# Generated deterministically by seda-macro-lef-normalizer-v1; recipe orfs-ng45-fakeram-metal3-coupledl2-pg-v1.
VERSION 5.8 ;
BUSBITCHARS "[]" ;
DIVIDERCHAR "/" ;

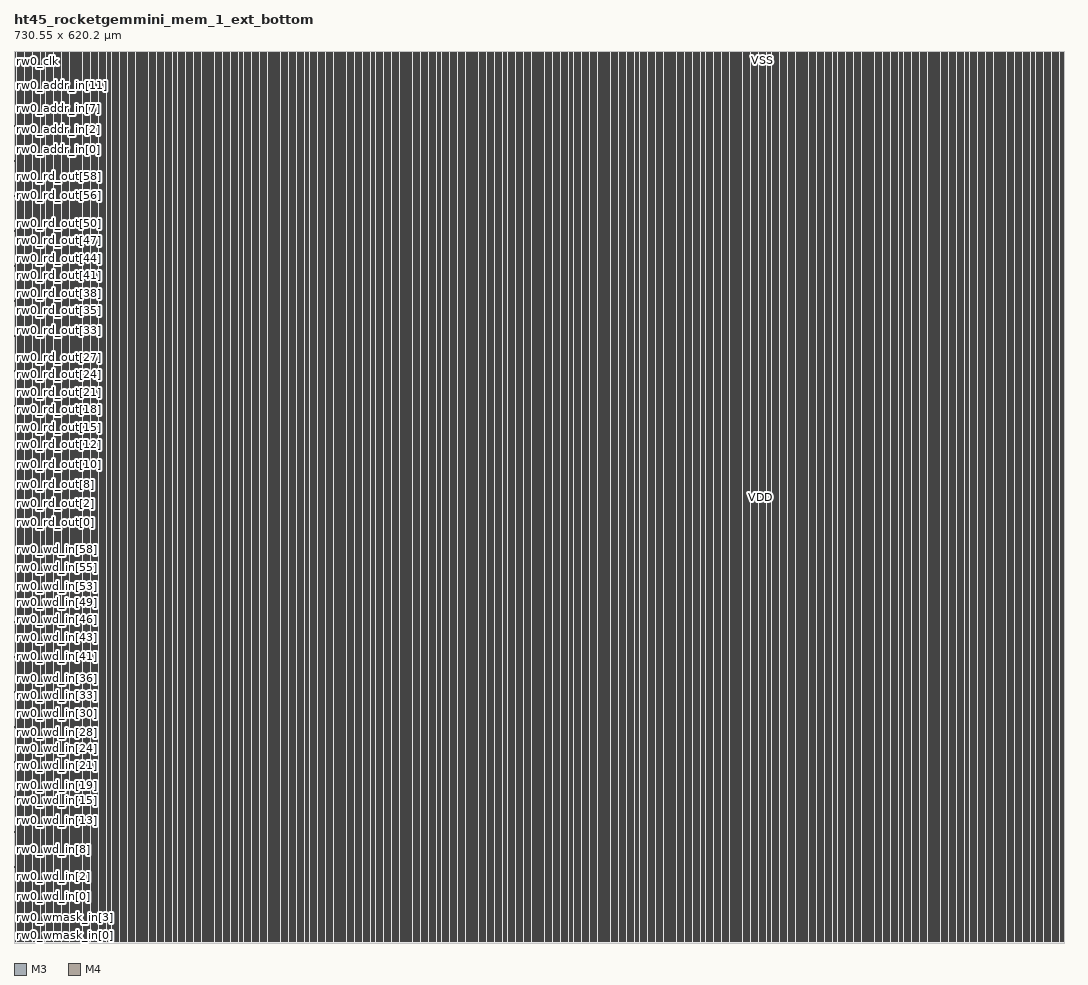
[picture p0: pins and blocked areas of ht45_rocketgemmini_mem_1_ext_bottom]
MACRO ht45_rocketgemmini_mem_1_ext_bottom
  FOREIGN ht45_rocketgemmini_mem_1_ext_bottom 0 0 ;
  CLASS BLOCK ;
  ORIGIN 0 0 ;
  SIZE 730.55 BY 620.2 ;
  SYMMETRY X Y R90 ;
  PIN rw0_wmask_in[0]
    DIRECTION INPUT ;
    USE SIGNAL ;
    SHAPE ABUTMENT ;
    PORT
      LAYER M3 ;
      RECT 0 0.035 0.07 0.105 ;
    END
  END rw0_wmask_in[0]
  PIN rw0_wmask_in[1]
    DIRECTION INPUT ;
    USE SIGNAL ;
    SHAPE ABUTMENT ;
    PORT
      LAYER M3 ;
      RECT 0 4.095 0.07 4.165 ;
    END
  END rw0_wmask_in[1]
  PIN rw0_wmask_in[2]
    DIRECTION INPUT ;
    USE SIGNAL ;
    SHAPE ABUTMENT ;
    PORT
      LAYER M3 ;
      RECT 0 8.155 0.07 8.225 ;
    END
  END rw0_wmask_in[2]
  PIN rw0_wmask_in[3]
    DIRECTION INPUT ;
    USE SIGNAL ;
    SHAPE ABUTMENT ;
    PORT
      LAYER M3 ;
      RECT 0 12.215 0.07 12.285 ;
    END
  END rw0_wmask_in[3]
  PIN rw0_wmask_in[4]
    DIRECTION INPUT ;
    USE SIGNAL ;
    SHAPE ABUTMENT ;
    PORT
      LAYER M3 ;
      RECT 0 16.275 0.07 16.345 ;
    END
  END rw0_wmask_in[4]
  PIN rw0_wmask_in[5]
    DIRECTION INPUT ;
    USE SIGNAL ;
    SHAPE ABUTMENT ;
    PORT
      LAYER M3 ;
      RECT 0 20.335 0.07 20.405 ;
    END
  END rw0_wmask_in[5]
  PIN rw0_wmask_in[6]
    DIRECTION INPUT ;
    USE SIGNAL ;
    SHAPE ABUTMENT ;
    PORT
      LAYER M3 ;
      RECT 0 24.395 0.07 24.465 ;
    END
  END rw0_wmask_in[6]
  PIN rw0_wmask_in[7]
    DIRECTION INPUT ;
    USE SIGNAL ;
    SHAPE ABUTMENT ;
    PORT
      LAYER M3 ;
      RECT 0 28.455 0.07 28.525 ;
    END
  END rw0_wmask_in[7]
  PIN rw0_wd_in[0]
    DIRECTION INPUT ;
    USE SIGNAL ;
    SHAPE ABUTMENT ;
    PORT
      LAYER M3 ;
      RECT 0 32.515 0.07 32.585 ;
    END
  END rw0_wd_in[0]
  PIN rw0_wd_in[1]
    DIRECTION INPUT ;
    USE SIGNAL ;
    SHAPE ABUTMENT ;
    PORT
      LAYER M3 ;
      RECT 0 36.575 0.07 36.645 ;
    END
  END rw0_wd_in[1]
  PIN rw0_wd_in[2]
    DIRECTION INPUT ;
    USE SIGNAL ;
    SHAPE ABUTMENT ;
    PORT
      LAYER M3 ;
      RECT 0 40.635 0.07 40.705 ;
    END
  END rw0_wd_in[2]
  PIN rw0_wd_in[3]
    DIRECTION INPUT ;
    USE SIGNAL ;
    SHAPE ABUTMENT ;
    PORT
      LAYER M3 ;
      RECT 0 44.695 0.07 44.765 ;
    END
  END rw0_wd_in[3]
  PIN rw0_wd_in[4]
    DIRECTION INPUT ;
    USE SIGNAL ;
    SHAPE ABUTMENT ;
    PORT
      LAYER M3 ;
      RECT 0 48.755 0.07 48.825 ;
    END
  END rw0_wd_in[4]
  PIN rw0_wd_in[5]
    DIRECTION INPUT ;
    USE SIGNAL ;
    SHAPE ABUTMENT ;
    PORT
      LAYER M3 ;
      RECT 0 52.815 0.07 52.885 ;
    END
  END rw0_wd_in[5]
  PIN rw0_wd_in[6]
    DIRECTION INPUT ;
    USE SIGNAL ;
    SHAPE ABUTMENT ;
    PORT
      LAYER M3 ;
      RECT 0 56.875 0.07 56.945 ;
    END
  END rw0_wd_in[6]
  PIN rw0_wd_in[7]
    DIRECTION INPUT ;
    USE SIGNAL ;
    SHAPE ABUTMENT ;
    PORT
      LAYER M3 ;
      RECT 0 60.935 0.07 61.005 ;
    END
  END rw0_wd_in[7]
  PIN rw0_wd_in[8]
    DIRECTION INPUT ;
    USE SIGNAL ;
    SHAPE ABUTMENT ;
    PORT
      LAYER M3 ;
      RECT 0 64.995 0.07 65.065 ;
    END
  END rw0_wd_in[8]
  PIN rw0_wd_in[9]
    DIRECTION INPUT ;
    USE SIGNAL ;
    SHAPE ABUTMENT ;
    PORT
      LAYER M3 ;
      RECT 0 69.055 0.07 69.125 ;
    END
  END rw0_wd_in[9]
  PIN rw0_wd_in[10]
    DIRECTION INPUT ;
    USE SIGNAL ;
    SHAPE ABUTMENT ;
    PORT
      LAYER M3 ;
      RECT 0 73.115 0.07 73.185 ;
    END
  END rw0_wd_in[10]
  PIN rw0_wd_in[11]
    DIRECTION INPUT ;
    USE SIGNAL ;
    SHAPE ABUTMENT ;
    PORT
      LAYER M3 ;
      RECT 0 77.175 0.07 77.245 ;
    END
  END rw0_wd_in[11]
  PIN rw0_wd_in[12]
    DIRECTION INPUT ;
    USE SIGNAL ;
    SHAPE ABUTMENT ;
    PORT
      LAYER M3 ;
      RECT 0 81.235 0.07 81.305 ;
    END
  END rw0_wd_in[12]
  PIN rw0_wd_in[13]
    DIRECTION INPUT ;
    USE SIGNAL ;
    SHAPE ABUTMENT ;
    PORT
      LAYER M3 ;
      RECT 0 85.295 0.07 85.365 ;
    END
  END rw0_wd_in[13]
  PIN rw0_wd_in[14]
    DIRECTION INPUT ;
    USE SIGNAL ;
    SHAPE ABUTMENT ;
    PORT
      LAYER M3 ;
      RECT 0 89.355 0.07 89.425 ;
    END
  END rw0_wd_in[14]
  PIN rw0_wd_in[15]
    DIRECTION INPUT ;
    USE SIGNAL ;
    SHAPE ABUTMENT ;
    PORT
      LAYER M3 ;
      RECT 0 93.415 0.07 93.485 ;
    END
  END rw0_wd_in[15]
  PIN rw0_wd_in[16]
    DIRECTION INPUT ;
    USE SIGNAL ;
    SHAPE ABUTMENT ;
    PORT
      LAYER M3 ;
      RECT 0 97.475 0.07 97.545 ;
    END
  END rw0_wd_in[16]
  PIN rw0_wd_in[17]
    DIRECTION INPUT ;
    USE SIGNAL ;
    SHAPE ABUTMENT ;
    PORT
      LAYER M3 ;
      RECT 0 101.535 0.07 101.605 ;
    END
  END rw0_wd_in[17]
  PIN rw0_wd_in[18]
    DIRECTION INPUT ;
    USE SIGNAL ;
    SHAPE ABUTMENT ;
    PORT
      LAYER M3 ;
      RECT 0 105.595 0.07 105.665 ;
    END
  END rw0_wd_in[18]
  PIN rw0_wd_in[19]
    DIRECTION INPUT ;
    USE SIGNAL ;
    SHAPE ABUTMENT ;
    PORT
      LAYER M3 ;
      RECT 0 109.655 0.07 109.725 ;
    END
  END rw0_wd_in[19]
  PIN rw0_wd_in[20]
    DIRECTION INPUT ;
    USE SIGNAL ;
    SHAPE ABUTMENT ;
    PORT
      LAYER M3 ;
      RECT 0 113.715 0.07 113.785 ;
    END
  END rw0_wd_in[20]
  PIN rw0_wd_in[21]
    DIRECTION INPUT ;
    USE SIGNAL ;
    SHAPE ABUTMENT ;
    PORT
      LAYER M3 ;
      RECT 0 117.775 0.07 117.845 ;
    END
  END rw0_wd_in[21]
  PIN rw0_wd_in[22]
    DIRECTION INPUT ;
    USE SIGNAL ;
    SHAPE ABUTMENT ;
    PORT
      LAYER M3 ;
      RECT 0 121.835 0.07 121.905 ;
    END
  END rw0_wd_in[22]
  PIN rw0_wd_in[23]
    DIRECTION INPUT ;
    USE SIGNAL ;
    SHAPE ABUTMENT ;
    PORT
      LAYER M3 ;
      RECT 0 125.895 0.07 125.965 ;
    END
  END rw0_wd_in[23]
  PIN rw0_wd_in[24]
    DIRECTION INPUT ;
    USE SIGNAL ;
    SHAPE ABUTMENT ;
    PORT
      LAYER M3 ;
      RECT 0 129.955 0.07 130.025 ;
    END
  END rw0_wd_in[24]
  PIN rw0_wd_in[25]
    DIRECTION INPUT ;
    USE SIGNAL ;
    SHAPE ABUTMENT ;
    PORT
      LAYER M3 ;
      RECT 0 134.015 0.07 134.085 ;
    END
  END rw0_wd_in[25]
  PIN rw0_wd_in[26]
    DIRECTION INPUT ;
    USE SIGNAL ;
    SHAPE ABUTMENT ;
    PORT
      LAYER M3 ;
      RECT 0 138.075 0.07 138.145 ;
    END
  END rw0_wd_in[26]
  PIN rw0_wd_in[27]
    DIRECTION INPUT ;
    USE SIGNAL ;
    SHAPE ABUTMENT ;
    PORT
      LAYER M3 ;
      RECT 0 142.135 0.07 142.205 ;
    END
  END rw0_wd_in[27]
  PIN rw0_wd_in[28]
    DIRECTION INPUT ;
    USE SIGNAL ;
    SHAPE ABUTMENT ;
    PORT
      LAYER M3 ;
      RECT 0 146.195 0.07 146.265 ;
    END
  END rw0_wd_in[28]
  PIN rw0_wd_in[29]
    DIRECTION INPUT ;
    USE SIGNAL ;
    SHAPE ABUTMENT ;
    PORT
      LAYER M3 ;
      RECT 0 150.255 0.07 150.325 ;
    END
  END rw0_wd_in[29]
  PIN rw0_wd_in[30]
    DIRECTION INPUT ;
    USE SIGNAL ;
    SHAPE ABUTMENT ;
    PORT
      LAYER M3 ;
      RECT 0 154.315 0.07 154.385 ;
    END
  END rw0_wd_in[30]
  PIN rw0_wd_in[31]
    DIRECTION INPUT ;
    USE SIGNAL ;
    SHAPE ABUTMENT ;
    PORT
      LAYER M3 ;
      RECT 0 158.375 0.07 158.445 ;
    END
  END rw0_wd_in[31]
  PIN rw0_wd_in[32]
    DIRECTION INPUT ;
    USE SIGNAL ;
    SHAPE ABUTMENT ;
    PORT
      LAYER M3 ;
      RECT 0 162.435 0.07 162.505 ;
    END
  END rw0_wd_in[32]
  PIN rw0_wd_in[33]
    DIRECTION INPUT ;
    USE SIGNAL ;
    SHAPE ABUTMENT ;
    PORT
      LAYER M3 ;
      RECT 0 166.495 0.07 166.565 ;
    END
  END rw0_wd_in[33]
  PIN rw0_wd_in[34]
    DIRECTION INPUT ;
    USE SIGNAL ;
    SHAPE ABUTMENT ;
    PORT
      LAYER M3 ;
      RECT 0 170.555 0.07 170.625 ;
    END
  END rw0_wd_in[34]
  PIN rw0_wd_in[35]
    DIRECTION INPUT ;
    USE SIGNAL ;
    SHAPE ABUTMENT ;
    PORT
      LAYER M3 ;
      RECT 0 174.615 0.07 174.685 ;
    END
  END rw0_wd_in[35]
  PIN rw0_wd_in[36]
    DIRECTION INPUT ;
    USE SIGNAL ;
    SHAPE ABUTMENT ;
    PORT
      LAYER M3 ;
      RECT 0 178.675 0.07 178.745 ;
    END
  END rw0_wd_in[36]
  PIN rw0_wd_in[37]
    DIRECTION INPUT ;
    USE SIGNAL ;
    SHAPE ABUTMENT ;
    PORT
      LAYER M3 ;
      RECT 0 182.735 0.07 182.805 ;
    END
  END rw0_wd_in[37]
  PIN rw0_wd_in[38]
    DIRECTION INPUT ;
    USE SIGNAL ;
    SHAPE ABUTMENT ;
    PORT
      LAYER M3 ;
      RECT 0 186.795 0.07 186.865 ;
    END
  END rw0_wd_in[38]
  PIN rw0_wd_in[39]
    DIRECTION INPUT ;
    USE SIGNAL ;
    SHAPE ABUTMENT ;
    PORT
      LAYER M3 ;
      RECT 0 190.855 0.07 190.925 ;
    END
  END rw0_wd_in[39]
  PIN rw0_wd_in[40]
    DIRECTION INPUT ;
    USE SIGNAL ;
    SHAPE ABUTMENT ;
    PORT
      LAYER M3 ;
      RECT 0 194.915 0.07 194.985 ;
    END
  END rw0_wd_in[40]
  PIN rw0_wd_in[41]
    DIRECTION INPUT ;
    USE SIGNAL ;
    SHAPE ABUTMENT ;
    PORT
      LAYER M3 ;
      RECT 0 198.975 0.07 199.045 ;
    END
  END rw0_wd_in[41]
  PIN rw0_wd_in[42]
    DIRECTION INPUT ;
    USE SIGNAL ;
    SHAPE ABUTMENT ;
    PORT
      LAYER M3 ;
      RECT 0 203.035 0.07 203.105 ;
    END
  END rw0_wd_in[42]
  PIN rw0_wd_in[43]
    DIRECTION INPUT ;
    USE SIGNAL ;
    SHAPE ABUTMENT ;
    PORT
      LAYER M3 ;
      RECT 0 207.095 0.07 207.165 ;
    END
  END rw0_wd_in[43]
  PIN rw0_wd_in[44]
    DIRECTION INPUT ;
    USE SIGNAL ;
    SHAPE ABUTMENT ;
    PORT
      LAYER M3 ;
      RECT 0 211.155 0.07 211.225 ;
    END
  END rw0_wd_in[44]
  PIN rw0_wd_in[45]
    DIRECTION INPUT ;
    USE SIGNAL ;
    SHAPE ABUTMENT ;
    PORT
      LAYER M3 ;
      RECT 0 215.215 0.07 215.285 ;
    END
  END rw0_wd_in[45]
  PIN rw0_wd_in[46]
    DIRECTION INPUT ;
    USE SIGNAL ;
    SHAPE ABUTMENT ;
    PORT
      LAYER M3 ;
      RECT 0 219.275 0.07 219.345 ;
    END
  END rw0_wd_in[46]
  PIN rw0_wd_in[47]
    DIRECTION INPUT ;
    USE SIGNAL ;
    SHAPE ABUTMENT ;
    PORT
      LAYER M3 ;
      RECT 0 223.335 0.07 223.405 ;
    END
  END rw0_wd_in[47]
  PIN rw0_wd_in[48]
    DIRECTION INPUT ;
    USE SIGNAL ;
    SHAPE ABUTMENT ;
    PORT
      LAYER M3 ;
      RECT 0 227.395 0.07 227.465 ;
    END
  END rw0_wd_in[48]
  PIN rw0_wd_in[49]
    DIRECTION INPUT ;
    USE SIGNAL ;
    SHAPE ABUTMENT ;
    PORT
      LAYER M3 ;
      RECT 0 231.455 0.07 231.525 ;
    END
  END rw0_wd_in[49]
  PIN rw0_wd_in[50]
    DIRECTION INPUT ;
    USE SIGNAL ;
    SHAPE ABUTMENT ;
    PORT
      LAYER M3 ;
      RECT 0 235.515 0.07 235.585 ;
    END
  END rw0_wd_in[50]
  PIN rw0_wd_in[51]
    DIRECTION INPUT ;
    USE SIGNAL ;
    SHAPE ABUTMENT ;
    PORT
      LAYER M3 ;
      RECT 0 239.575 0.07 239.645 ;
    END
  END rw0_wd_in[51]
  PIN rw0_wd_in[52]
    DIRECTION INPUT ;
    USE SIGNAL ;
    SHAPE ABUTMENT ;
    PORT
      LAYER M3 ;
      RECT 0 243.635 0.07 243.705 ;
    END
  END rw0_wd_in[52]
  PIN rw0_wd_in[53]
    DIRECTION INPUT ;
    USE SIGNAL ;
    SHAPE ABUTMENT ;
    PORT
      LAYER M3 ;
      RECT 0 247.695 0.07 247.765 ;
    END
  END rw0_wd_in[53]
  PIN rw0_wd_in[54]
    DIRECTION INPUT ;
    USE SIGNAL ;
    SHAPE ABUTMENT ;
    PORT
      LAYER M3 ;
      RECT 0 251.755 0.07 251.825 ;
    END
  END rw0_wd_in[54]
  PIN rw0_wd_in[55]
    DIRECTION INPUT ;
    USE SIGNAL ;
    SHAPE ABUTMENT ;
    PORT
      LAYER M3 ;
      RECT 0 255.815 0.07 255.885 ;
    END
  END rw0_wd_in[55]
  PIN rw0_wd_in[56]
    DIRECTION INPUT ;
    USE SIGNAL ;
    SHAPE ABUTMENT ;
    PORT
      LAYER M3 ;
      RECT 0 259.875 0.07 259.945 ;
    END
  END rw0_wd_in[56]
  PIN rw0_wd_in[57]
    DIRECTION INPUT ;
    USE SIGNAL ;
    SHAPE ABUTMENT ;
    PORT
      LAYER M3 ;
      RECT 0 263.935 0.07 264.005 ;
    END
  END rw0_wd_in[57]
  PIN rw0_wd_in[58]
    DIRECTION INPUT ;
    USE SIGNAL ;
    SHAPE ABUTMENT ;
    PORT
      LAYER M3 ;
      RECT 0 267.995 0.07 268.065 ;
    END
  END rw0_wd_in[58]
  PIN rw0_wd_in[59]
    DIRECTION INPUT ;
    USE SIGNAL ;
    SHAPE ABUTMENT ;
    PORT
      LAYER M3 ;
      RECT 0 272.055 0.07 272.125 ;
    END
  END rw0_wd_in[59]
  PIN rw0_wd_in[60]
    DIRECTION INPUT ;
    USE SIGNAL ;
    SHAPE ABUTMENT ;
    PORT
      LAYER M3 ;
      RECT 0 276.115 0.07 276.185 ;
    END
  END rw0_wd_in[60]
  PIN rw0_wd_in[61]
    DIRECTION INPUT ;
    USE SIGNAL ;
    SHAPE ABUTMENT ;
    PORT
      LAYER M3 ;
      RECT 0 280.175 0.07 280.245 ;
    END
  END rw0_wd_in[61]
  PIN rw0_wd_in[62]
    DIRECTION INPUT ;
    USE SIGNAL ;
    SHAPE ABUTMENT ;
    PORT
      LAYER M3 ;
      RECT 0 284.235 0.07 284.305 ;
    END
  END rw0_wd_in[62]
  PIN rw0_wd_in[63]
    DIRECTION INPUT ;
    USE SIGNAL ;
    SHAPE ABUTMENT ;
    PORT
      LAYER M3 ;
      RECT 0 288.295 0.07 288.365 ;
    END
  END rw0_wd_in[63]
  PIN rw0_rd_out[0]
    DIRECTION OUTPUT ;
    USE SIGNAL ;
    SHAPE ABUTMENT ;
    PORT
      LAYER M3 ;
      RECT 0 292.355 0.07 292.425 ;
    END
  END rw0_rd_out[0]
  PIN rw0_rd_out[1]
    DIRECTION OUTPUT ;
    USE SIGNAL ;
    SHAPE ABUTMENT ;
    PORT
      LAYER M3 ;
      RECT 0 296.415 0.07 296.485 ;
    END
  END rw0_rd_out[1]
  PIN rw0_rd_out[2]
    DIRECTION OUTPUT ;
    USE SIGNAL ;
    SHAPE ABUTMENT ;
    PORT
      LAYER M3 ;
      RECT 0 300.475 0.07 300.545 ;
    END
  END rw0_rd_out[2]
  PIN rw0_rd_out[3]
    DIRECTION OUTPUT ;
    USE SIGNAL ;
    SHAPE ABUTMENT ;
    PORT
      LAYER M3 ;
      RECT 0 304.535 0.07 304.605 ;
    END
  END rw0_rd_out[3]
  PIN rw0_rd_out[4]
    DIRECTION OUTPUT ;
    USE SIGNAL ;
    SHAPE ABUTMENT ;
    PORT
      LAYER M3 ;
      RECT 0 308.595 0.07 308.665 ;
    END
  END rw0_rd_out[4]
  PIN rw0_rd_out[5]
    DIRECTION OUTPUT ;
    USE SIGNAL ;
    SHAPE ABUTMENT ;
    PORT
      LAYER M3 ;
      RECT 0 312.655 0.07 312.725 ;
    END
  END rw0_rd_out[5]
  PIN rw0_rd_out[6]
    DIRECTION OUTPUT ;
    USE SIGNAL ;
    SHAPE ABUTMENT ;
    PORT
      LAYER M3 ;
      RECT 0 316.715 0.07 316.785 ;
    END
  END rw0_rd_out[6]
  PIN rw0_rd_out[7]
    DIRECTION OUTPUT ;
    USE SIGNAL ;
    SHAPE ABUTMENT ;
    PORT
      LAYER M3 ;
      RECT 0 320.775 0.07 320.845 ;
    END
  END rw0_rd_out[7]
  PIN rw0_rd_out[8]
    DIRECTION OUTPUT ;
    USE SIGNAL ;
    SHAPE ABUTMENT ;
    PORT
      LAYER M3 ;
      RECT 0 324.835 0.07 324.905 ;
    END
  END rw0_rd_out[8]
  PIN rw0_rd_out[9]
    DIRECTION OUTPUT ;
    USE SIGNAL ;
    SHAPE ABUTMENT ;
    PORT
      LAYER M3 ;
      RECT 0 328.895 0.07 328.965 ;
    END
  END rw0_rd_out[9]
  PIN rw0_rd_out[10]
    DIRECTION OUTPUT ;
    USE SIGNAL ;
    SHAPE ABUTMENT ;
    PORT
      LAYER M3 ;
      RECT 0 332.955 0.07 333.025 ;
    END
  END rw0_rd_out[10]
  PIN rw0_rd_out[11]
    DIRECTION OUTPUT ;
    USE SIGNAL ;
    SHAPE ABUTMENT ;
    PORT
      LAYER M3 ;
      RECT 0 337.015 0.07 337.085 ;
    END
  END rw0_rd_out[11]
  PIN rw0_rd_out[12]
    DIRECTION OUTPUT ;
    USE SIGNAL ;
    SHAPE ABUTMENT ;
    PORT
      LAYER M3 ;
      RECT 0 341.075 0.07 341.145 ;
    END
  END rw0_rd_out[12]
  PIN rw0_rd_out[13]
    DIRECTION OUTPUT ;
    USE SIGNAL ;
    SHAPE ABUTMENT ;
    PORT
      LAYER M3 ;
      RECT 0 345.135 0.07 345.205 ;
    END
  END rw0_rd_out[13]
  PIN rw0_rd_out[14]
    DIRECTION OUTPUT ;
    USE SIGNAL ;
    SHAPE ABUTMENT ;
    PORT
      LAYER M3 ;
      RECT 0 349.195 0.07 349.265 ;
    END
  END rw0_rd_out[14]
  PIN rw0_rd_out[15]
    DIRECTION OUTPUT ;
    USE SIGNAL ;
    SHAPE ABUTMENT ;
    PORT
      LAYER M3 ;
      RECT 0 353.255 0.07 353.325 ;
    END
  END rw0_rd_out[15]
  PIN rw0_rd_out[16]
    DIRECTION OUTPUT ;
    USE SIGNAL ;
    SHAPE ABUTMENT ;
    PORT
      LAYER M3 ;
      RECT 0 357.315 0.07 357.385 ;
    END
  END rw0_rd_out[16]
  PIN rw0_rd_out[17]
    DIRECTION OUTPUT ;
    USE SIGNAL ;
    SHAPE ABUTMENT ;
    PORT
      LAYER M3 ;
      RECT 0 361.375 0.07 361.445 ;
    END
  END rw0_rd_out[17]
  PIN rw0_rd_out[18]
    DIRECTION OUTPUT ;
    USE SIGNAL ;
    SHAPE ABUTMENT ;
    PORT
      LAYER M3 ;
      RECT 0 365.435 0.07 365.505 ;
    END
  END rw0_rd_out[18]
  PIN rw0_rd_out[19]
    DIRECTION OUTPUT ;
    USE SIGNAL ;
    SHAPE ABUTMENT ;
    PORT
      LAYER M3 ;
      RECT 0 369.495 0.07 369.565 ;
    END
  END rw0_rd_out[19]
  PIN rw0_rd_out[20]
    DIRECTION OUTPUT ;
    USE SIGNAL ;
    SHAPE ABUTMENT ;
    PORT
      LAYER M3 ;
      RECT 0 373.555 0.07 373.625 ;
    END
  END rw0_rd_out[20]
  PIN rw0_rd_out[21]
    DIRECTION OUTPUT ;
    USE SIGNAL ;
    SHAPE ABUTMENT ;
    PORT
      LAYER M3 ;
      RECT 0 377.615 0.07 377.685 ;
    END
  END rw0_rd_out[21]
  PIN rw0_rd_out[22]
    DIRECTION OUTPUT ;
    USE SIGNAL ;
    SHAPE ABUTMENT ;
    PORT
      LAYER M3 ;
      RECT 0 381.675 0.07 381.745 ;
    END
  END rw0_rd_out[22]
  PIN rw0_rd_out[23]
    DIRECTION OUTPUT ;
    USE SIGNAL ;
    SHAPE ABUTMENT ;
    PORT
      LAYER M3 ;
      RECT 0 385.735 0.07 385.805 ;
    END
  END rw0_rd_out[23]
  PIN rw0_rd_out[24]
    DIRECTION OUTPUT ;
    USE SIGNAL ;
    SHAPE ABUTMENT ;
    PORT
      LAYER M3 ;
      RECT 0 389.795 0.07 389.865 ;
    END
  END rw0_rd_out[24]
  PIN rw0_rd_out[25]
    DIRECTION OUTPUT ;
    USE SIGNAL ;
    SHAPE ABUTMENT ;
    PORT
      LAYER M3 ;
      RECT 0 393.855 0.07 393.925 ;
    END
  END rw0_rd_out[25]
  PIN rw0_rd_out[26]
    DIRECTION OUTPUT ;
    USE SIGNAL ;
    SHAPE ABUTMENT ;
    PORT
      LAYER M3 ;
      RECT 0 397.915 0.07 397.985 ;
    END
  END rw0_rd_out[26]
  PIN rw0_rd_out[27]
    DIRECTION OUTPUT ;
    USE SIGNAL ;
    SHAPE ABUTMENT ;
    PORT
      LAYER M3 ;
      RECT 0 401.975 0.07 402.045 ;
    END
  END rw0_rd_out[27]
  PIN rw0_rd_out[28]
    DIRECTION OUTPUT ;
    USE SIGNAL ;
    SHAPE ABUTMENT ;
    PORT
      LAYER M3 ;
      RECT 0 406.035 0.07 406.105 ;
    END
  END rw0_rd_out[28]
  PIN rw0_rd_out[29]
    DIRECTION OUTPUT ;
    USE SIGNAL ;
    SHAPE ABUTMENT ;
    PORT
      LAYER M3 ;
      RECT 0 410.095 0.07 410.165 ;
    END
  END rw0_rd_out[29]
  PIN rw0_rd_out[30]
    DIRECTION OUTPUT ;
    USE SIGNAL ;
    SHAPE ABUTMENT ;
    PORT
      LAYER M3 ;
      RECT 0 414.155 0.07 414.225 ;
    END
  END rw0_rd_out[30]
  PIN rw0_rd_out[31]
    DIRECTION OUTPUT ;
    USE SIGNAL ;
    SHAPE ABUTMENT ;
    PORT
      LAYER M3 ;
      RECT 0 418.215 0.07 418.285 ;
    END
  END rw0_rd_out[31]
  PIN rw0_rd_out[32]
    DIRECTION OUTPUT ;
    USE SIGNAL ;
    SHAPE ABUTMENT ;
    PORT
      LAYER M3 ;
      RECT 0 422.275 0.07 422.345 ;
    END
  END rw0_rd_out[32]
  PIN rw0_rd_out[33]
    DIRECTION OUTPUT ;
    USE SIGNAL ;
    SHAPE ABUTMENT ;
    PORT
      LAYER M3 ;
      RECT 0 426.335 0.07 426.405 ;
    END
  END rw0_rd_out[33]
  PIN rw0_rd_out[34]
    DIRECTION OUTPUT ;
    USE SIGNAL ;
    SHAPE ABUTMENT ;
    PORT
      LAYER M3 ;
      RECT 0 430.395 0.07 430.465 ;
    END
  END rw0_rd_out[34]
  PIN rw0_rd_out[35]
    DIRECTION OUTPUT ;
    USE SIGNAL ;
    SHAPE ABUTMENT ;
    PORT
      LAYER M3 ;
      RECT 0 434.455 0.07 434.525 ;
    END
  END rw0_rd_out[35]
  PIN rw0_rd_out[36]
    DIRECTION OUTPUT ;
    USE SIGNAL ;
    SHAPE ABUTMENT ;
    PORT
      LAYER M3 ;
      RECT 0 438.515 0.07 438.585 ;
    END
  END rw0_rd_out[36]
  PIN rw0_rd_out[37]
    DIRECTION OUTPUT ;
    USE SIGNAL ;
    SHAPE ABUTMENT ;
    PORT
      LAYER M3 ;
      RECT 0 442.575 0.07 442.645 ;
    END
  END rw0_rd_out[37]
  PIN rw0_rd_out[38]
    DIRECTION OUTPUT ;
    USE SIGNAL ;
    SHAPE ABUTMENT ;
    PORT
      LAYER M3 ;
      RECT 0 446.635 0.07 446.705 ;
    END
  END rw0_rd_out[38]
  PIN rw0_rd_out[39]
    DIRECTION OUTPUT ;
    USE SIGNAL ;
    SHAPE ABUTMENT ;
    PORT
      LAYER M3 ;
      RECT 0 450.695 0.07 450.765 ;
    END
  END rw0_rd_out[39]
  PIN rw0_rd_out[40]
    DIRECTION OUTPUT ;
    USE SIGNAL ;
    SHAPE ABUTMENT ;
    PORT
      LAYER M3 ;
      RECT 0 454.755 0.07 454.825 ;
    END
  END rw0_rd_out[40]
  PIN rw0_rd_out[41]
    DIRECTION OUTPUT ;
    USE SIGNAL ;
    SHAPE ABUTMENT ;
    PORT
      LAYER M3 ;
      RECT 0 458.815 0.07 458.885 ;
    END
  END rw0_rd_out[41]
  PIN rw0_rd_out[42]
    DIRECTION OUTPUT ;
    USE SIGNAL ;
    SHAPE ABUTMENT ;
    PORT
      LAYER M3 ;
      RECT 0 462.875 0.07 462.945 ;
    END
  END rw0_rd_out[42]
  PIN rw0_rd_out[43]
    DIRECTION OUTPUT ;
    USE SIGNAL ;
    SHAPE ABUTMENT ;
    PORT
      LAYER M3 ;
      RECT 0 466.935 0.07 467.005 ;
    END
  END rw0_rd_out[43]
  PIN rw0_rd_out[44]
    DIRECTION OUTPUT ;
    USE SIGNAL ;
    SHAPE ABUTMENT ;
    PORT
      LAYER M3 ;
      RECT 0 470.995 0.07 471.065 ;
    END
  END rw0_rd_out[44]
  PIN rw0_rd_out[45]
    DIRECTION OUTPUT ;
    USE SIGNAL ;
    SHAPE ABUTMENT ;
    PORT
      LAYER M3 ;
      RECT 0 475.055 0.07 475.125 ;
    END
  END rw0_rd_out[45]
  PIN rw0_rd_out[46]
    DIRECTION OUTPUT ;
    USE SIGNAL ;
    SHAPE ABUTMENT ;
    PORT
      LAYER M3 ;
      RECT 0 479.115 0.07 479.185 ;
    END
  END rw0_rd_out[46]
  PIN rw0_rd_out[47]
    DIRECTION OUTPUT ;
    USE SIGNAL ;
    SHAPE ABUTMENT ;
    PORT
      LAYER M3 ;
      RECT 0 483.175 0.07 483.245 ;
    END
  END rw0_rd_out[47]
  PIN rw0_rd_out[48]
    DIRECTION OUTPUT ;
    USE SIGNAL ;
    SHAPE ABUTMENT ;
    PORT
      LAYER M3 ;
      RECT 0 487.235 0.07 487.305 ;
    END
  END rw0_rd_out[48]
  PIN rw0_rd_out[49]
    DIRECTION OUTPUT ;
    USE SIGNAL ;
    SHAPE ABUTMENT ;
    PORT
      LAYER M3 ;
      RECT 0 491.295 0.07 491.365 ;
    END
  END rw0_rd_out[49]
  PIN rw0_rd_out[50]
    DIRECTION OUTPUT ;
    USE SIGNAL ;
    SHAPE ABUTMENT ;
    PORT
      LAYER M3 ;
      RECT 0 495.355 0.07 495.425 ;
    END
  END rw0_rd_out[50]
  PIN rw0_rd_out[51]
    DIRECTION OUTPUT ;
    USE SIGNAL ;
    SHAPE ABUTMENT ;
    PORT
      LAYER M3 ;
      RECT 0 499.415 0.07 499.485 ;
    END
  END rw0_rd_out[51]
  PIN rw0_rd_out[52]
    DIRECTION OUTPUT ;
    USE SIGNAL ;
    SHAPE ABUTMENT ;
    PORT
      LAYER M3 ;
      RECT 0 503.475 0.07 503.545 ;
    END
  END rw0_rd_out[52]
  PIN rw0_rd_out[53]
    DIRECTION OUTPUT ;
    USE SIGNAL ;
    SHAPE ABUTMENT ;
    PORT
      LAYER M3 ;
      RECT 0 507.535 0.07 507.605 ;
    END
  END rw0_rd_out[53]
  PIN rw0_rd_out[54]
    DIRECTION OUTPUT ;
    USE SIGNAL ;
    SHAPE ABUTMENT ;
    PORT
      LAYER M3 ;
      RECT 0 511.595 0.07 511.665 ;
    END
  END rw0_rd_out[54]
  PIN rw0_rd_out[55]
    DIRECTION OUTPUT ;
    USE SIGNAL ;
    SHAPE ABUTMENT ;
    PORT
      LAYER M3 ;
      RECT 0 515.655 0.07 515.725 ;
    END
  END rw0_rd_out[55]
  PIN rw0_rd_out[56]
    DIRECTION OUTPUT ;
    USE SIGNAL ;
    SHAPE ABUTMENT ;
    PORT
      LAYER M3 ;
      RECT 0 519.715 0.07 519.785 ;
    END
  END rw0_rd_out[56]
  PIN rw0_rd_out[57]
    DIRECTION OUTPUT ;
    USE SIGNAL ;
    SHAPE ABUTMENT ;
    PORT
      LAYER M3 ;
      RECT 0 523.775 0.07 523.845 ;
    END
  END rw0_rd_out[57]
  PIN rw0_rd_out[58]
    DIRECTION OUTPUT ;
    USE SIGNAL ;
    SHAPE ABUTMENT ;
    PORT
      LAYER M3 ;
      RECT 0 527.835 0.07 527.905 ;
    END
  END rw0_rd_out[58]
  PIN rw0_rd_out[59]
    DIRECTION OUTPUT ;
    USE SIGNAL ;
    SHAPE ABUTMENT ;
    PORT
      LAYER M3 ;
      RECT 0 531.895 0.07 531.965 ;
    END
  END rw0_rd_out[59]
  PIN rw0_rd_out[60]
    DIRECTION OUTPUT ;
    USE SIGNAL ;
    SHAPE ABUTMENT ;
    PORT
      LAYER M3 ;
      RECT 0 535.955 0.07 536.025 ;
    END
  END rw0_rd_out[60]
  PIN rw0_rd_out[61]
    DIRECTION OUTPUT ;
    USE SIGNAL ;
    SHAPE ABUTMENT ;
    PORT
      LAYER M3 ;
      RECT 0 540.015 0.07 540.085 ;
    END
  END rw0_rd_out[61]
  PIN rw0_rd_out[62]
    DIRECTION OUTPUT ;
    USE SIGNAL ;
    SHAPE ABUTMENT ;
    PORT
      LAYER M3 ;
      RECT 0 544.075 0.07 544.145 ;
    END
  END rw0_rd_out[62]
  PIN rw0_rd_out[63]
    DIRECTION OUTPUT ;
    USE SIGNAL ;
    SHAPE ABUTMENT ;
    PORT
      LAYER M3 ;
      RECT 0 548.135 0.07 548.205 ;
    END
  END rw0_rd_out[63]
  PIN rw0_addr_in[0]
    DIRECTION INPUT ;
    USE SIGNAL ;
    SHAPE ABUTMENT ;
    PORT
      LAYER M3 ;
      RECT 0 552.195 0.07 552.265 ;
    END
  END rw0_addr_in[0]
  PIN rw0_addr_in[1]
    DIRECTION INPUT ;
    USE SIGNAL ;
    SHAPE ABUTMENT ;
    PORT
      LAYER M3 ;
      RECT 0 556.255 0.07 556.325 ;
    END
  END rw0_addr_in[1]
  PIN rw0_addr_in[2]
    DIRECTION INPUT ;
    USE SIGNAL ;
    SHAPE ABUTMENT ;
    PORT
      LAYER M3 ;
      RECT 0 560.315 0.07 560.385 ;
    END
  END rw0_addr_in[2]
  PIN rw0_addr_in[3]
    DIRECTION INPUT ;
    USE SIGNAL ;
    SHAPE ABUTMENT ;
    PORT
      LAYER M3 ;
      RECT 0 564.375 0.07 564.445 ;
    END
  END rw0_addr_in[3]
  PIN rw0_addr_in[4]
    DIRECTION INPUT ;
    USE SIGNAL ;
    SHAPE ABUTMENT ;
    PORT
      LAYER M3 ;
      RECT 0 568.435 0.07 568.505 ;
    END
  END rw0_addr_in[4]
  PIN rw0_addr_in[5]
    DIRECTION INPUT ;
    USE SIGNAL ;
    SHAPE ABUTMENT ;
    PORT
      LAYER M3 ;
      RECT 0 572.495 0.07 572.565 ;
    END
  END rw0_addr_in[5]
  PIN rw0_addr_in[6]
    DIRECTION INPUT ;
    USE SIGNAL ;
    SHAPE ABUTMENT ;
    PORT
      LAYER M3 ;
      RECT 0 576.555 0.07 576.625 ;
    END
  END rw0_addr_in[6]
  PIN rw0_addr_in[7]
    DIRECTION INPUT ;
    USE SIGNAL ;
    SHAPE ABUTMENT ;
    PORT
      LAYER M3 ;
      RECT 0 580.615 0.07 580.685 ;
    END
  END rw0_addr_in[7]
  PIN rw0_addr_in[8]
    DIRECTION INPUT ;
    USE SIGNAL ;
    SHAPE ABUTMENT ;
    PORT
      LAYER M3 ;
      RECT 0 584.675 0.07 584.745 ;
    END
  END rw0_addr_in[8]
  PIN rw0_addr_in[9]
    DIRECTION INPUT ;
    USE SIGNAL ;
    SHAPE ABUTMENT ;
    PORT
      LAYER M3 ;
      RECT 0 588.735 0.07 588.805 ;
    END
  END rw0_addr_in[9]
  PIN rw0_addr_in[10]
    DIRECTION INPUT ;
    USE SIGNAL ;
    SHAPE ABUTMENT ;
    PORT
      LAYER M3 ;
      RECT 0 592.795 0.07 592.865 ;
    END
  END rw0_addr_in[10]
  PIN rw0_addr_in[11]
    DIRECTION INPUT ;
    USE SIGNAL ;
    SHAPE ABUTMENT ;
    PORT
      LAYER M3 ;
      RECT 0 596.855 0.07 596.925 ;
    END
  END rw0_addr_in[11]
  PIN rw0_addr_in[12]
    DIRECTION INPUT ;
    USE SIGNAL ;
    SHAPE ABUTMENT ;
    PORT
      LAYER M3 ;
      RECT 0 600.915 0.07 600.985 ;
    END
  END rw0_addr_in[12]
  PIN rw0_we_in
    DIRECTION INPUT ;
    USE SIGNAL ;
    SHAPE ABUTMENT ;
    PORT
      LAYER M3 ;
      RECT 0 604.975 0.07 605.045 ;
    END
  END rw0_we_in
  PIN rw0_ce_in
    DIRECTION INPUT ;
    USE SIGNAL ;
    SHAPE ABUTMENT ;
    PORT
      LAYER M3 ;
      RECT 0 609.035 0.07 609.105 ;
    END
  END rw0_ce_in
  PIN rw0_clk
    DIRECTION INPUT ;
    USE SIGNAL ;
    SHAPE ABUTMENT ;
    PORT
      LAYER M3 ;
      RECT 0 613.095 0.07 613.165 ;
    END
  END rw0_clk
  PIN VSS
    DIRECTION INOUT ;
    USE GROUND ;
    PORT
      LAYER M4 ;
      RECT 1 0.84 1.28 619.36 ;
      RECT 3.24 0.84 3.52 619.36 ;
      RECT 5.48 0.84 5.76 619.36 ;
      RECT 7.72 0.84 8 619.36 ;
      RECT 9.96 0.84 10.24 619.36 ;
      RECT 12.2 0.84 12.48 619.36 ;
      RECT 14.44 0.84 14.72 619.36 ;
      RECT 16.68 0.84 16.96 619.36 ;
      RECT 18.92 0.84 19.2 619.36 ;
      RECT 21.16 0.84 21.44 619.36 ;
      RECT 23.4 0.84 23.68 619.36 ;
      RECT 25.64 0.84 25.92 619.36 ;
      RECT 27.88 0.84 28.16 619.36 ;
      RECT 30.12 0.84 30.4 619.36 ;
      RECT 32.36 0.84 32.64 619.36 ;
      RECT 34.6 0.84 34.88 619.36 ;
      RECT 36.84 0.84 37.12 619.36 ;
      RECT 39.08 0.84 39.36 619.36 ;
      RECT 41.32 0.84 41.6 619.36 ;
      RECT 43.56 0.84 43.84 619.36 ;
      RECT 45.8 0.84 46.08 619.36 ;
      RECT 48.04 0.84 48.32 619.36 ;
      RECT 50.28 0.84 50.56 619.36 ;
      RECT 52.52 0.84 52.8 619.36 ;
      RECT 54.76 0.84 55.04 619.36 ;
      RECT 57 0.84 57.28 619.36 ;
      RECT 59.24 0.84 59.52 619.36 ;
      RECT 61.48 0.84 61.76 619.36 ;
      RECT 63.72 0.84 64 619.36 ;
      RECT 65.96 0.84 66.24 619.36 ;
      RECT 68.2 0.84 68.48 619.36 ;
      RECT 70.44 0.84 70.72 619.36 ;
      RECT 72.68 0.84 72.96 619.36 ;
      RECT 74.92 0.84 75.2 619.36 ;
      RECT 77.16 0.84 77.44 619.36 ;
      RECT 79.4 0.84 79.68 619.36 ;
      RECT 81.64 0.84 81.92 619.36 ;
      RECT 83.88 0.84 84.16 619.36 ;
      RECT 86.12 0.84 86.4 619.36 ;
      RECT 88.36 0.84 88.64 619.36 ;
      RECT 90.6 0.84 90.88 619.36 ;
      RECT 92.84 0.84 93.12 619.36 ;
      RECT 95.08 0.84 95.36 619.36 ;
      RECT 97.32 0.84 97.6 619.36 ;
      RECT 99.56 0.84 99.84 619.36 ;
      RECT 101.8 0.84 102.08 619.36 ;
      RECT 104.04 0.84 104.32 619.36 ;
      RECT 106.28 0.84 106.56 619.36 ;
      RECT 108.52 0.84 108.8 619.36 ;
      RECT 110.76 0.84 111.04 619.36 ;
      RECT 113 0.84 113.28 619.36 ;
      RECT 115.24 0.84 115.52 619.36 ;
      RECT 117.48 0.84 117.76 619.36 ;
      RECT 119.72 0.84 120 619.36 ;
      RECT 121.96 0.84 122.24 619.36 ;
      RECT 124.2 0.84 124.48 619.36 ;
      RECT 126.44 0.84 126.72 619.36 ;
      RECT 128.68 0.84 128.96 619.36 ;
      RECT 130.92 0.84 131.2 619.36 ;
      RECT 133.16 0.84 133.44 619.36 ;
      RECT 135.4 0.84 135.68 619.36 ;
      RECT 137.64 0.84 137.92 619.36 ;
      RECT 139.88 0.84 140.16 619.36 ;
      RECT 142.12 0.84 142.4 619.36 ;
      RECT 144.36 0.84 144.64 619.36 ;
      RECT 146.6 0.84 146.88 619.36 ;
      RECT 148.84 0.84 149.12 619.36 ;
      RECT 151.08 0.84 151.36 619.36 ;
      RECT 153.32 0.84 153.6 619.36 ;
      RECT 155.56 0.84 155.84 619.36 ;
      RECT 157.8 0.84 158.08 619.36 ;
      RECT 160.04 0.84 160.32 619.36 ;
      RECT 162.28 0.84 162.56 619.36 ;
      RECT 164.52 0.84 164.8 619.36 ;
      RECT 166.76 0.84 167.04 619.36 ;
      RECT 169 0.84 169.28 619.36 ;
      RECT 171.24 0.84 171.52 619.36 ;
      RECT 173.48 0.84 173.76 619.36 ;
      RECT 175.72 0.84 176 619.36 ;
      RECT 177.96 0.84 178.24 619.36 ;
      RECT 180.2 0.84 180.48 619.36 ;
      RECT 182.44 0.84 182.72 619.36 ;
      RECT 184.68 0.84 184.96 619.36 ;
      RECT 186.92 0.84 187.2 619.36 ;
      RECT 189.16 0.84 189.44 619.36 ;
      RECT 191.4 0.84 191.68 619.36 ;
      RECT 193.64 0.84 193.92 619.36 ;
      RECT 195.88 0.84 196.16 619.36 ;
      RECT 198.12 0.84 198.4 619.36 ;
      RECT 200.36 0.84 200.64 619.36 ;
      RECT 202.6 0.84 202.88 619.36 ;
      RECT 204.84 0.84 205.12 619.36 ;
      RECT 207.08 0.84 207.36 619.36 ;
      RECT 209.32 0.84 209.6 619.36 ;
      RECT 211.56 0.84 211.84 619.36 ;
      RECT 213.8 0.84 214.08 619.36 ;
      RECT 216.04 0.84 216.32 619.36 ;
      RECT 218.28 0.84 218.56 619.36 ;
      RECT 220.52 0.84 220.8 619.36 ;
      RECT 222.76 0.84 223.04 619.36 ;
      RECT 225 0.84 225.28 619.36 ;
      RECT 227.24 0.84 227.52 619.36 ;
      RECT 229.48 0.84 229.76 619.36 ;
      RECT 231.72 0.84 232 619.36 ;
      RECT 233.96 0.84 234.24 619.36 ;
      RECT 236.2 0.84 236.48 619.36 ;
      RECT 238.44 0.84 238.72 619.36 ;
      RECT 240.68 0.84 240.96 619.36 ;
      RECT 242.92 0.84 243.2 619.36 ;
      RECT 245.16 0.84 245.44 619.36 ;
      RECT 247.4 0.84 247.68 619.36 ;
      RECT 249.64 0.84 249.92 619.36 ;
      RECT 251.88 0.84 252.16 619.36 ;
      RECT 254.12 0.84 254.4 619.36 ;
      RECT 256.36 0.84 256.64 619.36 ;
      RECT 258.6 0.84 258.88 619.36 ;
      RECT 260.84 0.84 261.12 619.36 ;
      RECT 263.08 0.84 263.36 619.36 ;
      RECT 265.32 0.84 265.6 619.36 ;
      RECT 267.56 0.84 267.84 619.36 ;
      RECT 269.8 0.84 270.08 619.36 ;
      RECT 272.04 0.84 272.32 619.36 ;
      RECT 274.28 0.84 274.56 619.36 ;
      RECT 276.52 0.84 276.8 619.36 ;
      RECT 278.76 0.84 279.04 619.36 ;
      RECT 281 0.84 281.28 619.36 ;
      RECT 283.24 0.84 283.52 619.36 ;
      RECT 285.48 0.84 285.76 619.36 ;
      RECT 287.72 0.84 288 619.36 ;
      RECT 289.96 0.84 290.24 619.36 ;
      RECT 292.2 0.84 292.48 619.36 ;
      RECT 294.44 0.84 294.72 619.36 ;
      RECT 296.68 0.84 296.96 619.36 ;
      RECT 298.92 0.84 299.2 619.36 ;
      RECT 301.16 0.84 301.44 619.36 ;
      RECT 303.4 0.84 303.68 619.36 ;
      RECT 305.64 0.84 305.92 619.36 ;
      RECT 307.88 0.84 308.16 619.36 ;
      RECT 310.12 0.84 310.4 619.36 ;
      RECT 312.36 0.84 312.64 619.36 ;
      RECT 314.6 0.84 314.88 619.36 ;
      RECT 316.84 0.84 317.12 619.36 ;
      RECT 319.08 0.84 319.36 619.36 ;
      RECT 321.32 0.84 321.6 619.36 ;
      RECT 323.56 0.84 323.84 619.36 ;
      RECT 325.8 0.84 326.08 619.36 ;
      RECT 328.04 0.84 328.32 619.36 ;
      RECT 330.28 0.84 330.56 619.36 ;
      RECT 332.52 0.84 332.8 619.36 ;
      RECT 334.76 0.84 335.04 619.36 ;
      RECT 337 0.84 337.28 619.36 ;
      RECT 339.24 0.84 339.52 619.36 ;
      RECT 341.48 0.84 341.76 619.36 ;
      RECT 343.72 0.84 344 619.36 ;
      RECT 345.96 0.84 346.24 619.36 ;
      RECT 348.2 0.84 348.48 619.36 ;
      RECT 350.44 0.84 350.72 619.36 ;
      RECT 352.68 0.84 352.96 619.36 ;
      RECT 354.92 0.84 355.2 619.36 ;
      RECT 357.16 0.84 357.44 619.36 ;
      RECT 359.4 0.84 359.68 619.36 ;
      RECT 361.64 0.84 361.92 619.36 ;
      RECT 363.88 0.84 364.16 619.36 ;
      RECT 366.12 0.84 366.4 619.36 ;
      RECT 368.36 0.84 368.64 619.36 ;
      RECT 370.6 0.84 370.88 619.36 ;
      RECT 372.84 0.84 373.12 619.36 ;
      RECT 375.08 0.84 375.36 619.36 ;
      RECT 377.32 0.84 377.6 619.36 ;
      RECT 379.56 0.84 379.84 619.36 ;
      RECT 381.8 0.84 382.08 619.36 ;
      RECT 384.04 0.84 384.32 619.36 ;
      RECT 386.28 0.84 386.56 619.36 ;
      RECT 388.52 0.84 388.8 619.36 ;
      RECT 390.76 0.84 391.04 619.36 ;
      RECT 393 0.84 393.28 619.36 ;
      RECT 395.24 0.84 395.52 619.36 ;
      RECT 397.48 0.84 397.76 619.36 ;
      RECT 399.72 0.84 400 619.36 ;
      RECT 401.96 0.84 402.24 619.36 ;
      RECT 404.2 0.84 404.48 619.36 ;
      RECT 406.44 0.84 406.72 619.36 ;
      RECT 408.68 0.84 408.96 619.36 ;
      RECT 410.92 0.84 411.2 619.36 ;
      RECT 413.16 0.84 413.44 619.36 ;
      RECT 415.4 0.84 415.68 619.36 ;
      RECT 417.64 0.84 417.92 619.36 ;
      RECT 419.88 0.84 420.16 619.36 ;
      RECT 422.12 0.84 422.4 619.36 ;
      RECT 424.36 0.84 424.64 619.36 ;
      RECT 426.6 0.84 426.88 619.36 ;
      RECT 428.84 0.84 429.12 619.36 ;
      RECT 431.08 0.84 431.36 619.36 ;
      RECT 433.32 0.84 433.6 619.36 ;
      RECT 435.56 0.84 435.84 619.36 ;
      RECT 437.8 0.84 438.08 619.36 ;
      RECT 440.04 0.84 440.32 619.36 ;
      RECT 442.28 0.84 442.56 619.36 ;
      RECT 444.52 0.84 444.8 619.36 ;
      RECT 446.76 0.84 447.04 619.36 ;
      RECT 449 0.84 449.28 619.36 ;
      RECT 451.24 0.84 451.52 619.36 ;
      RECT 453.48 0.84 453.76 619.36 ;
      RECT 455.72 0.84 456 619.36 ;
      RECT 457.96 0.84 458.24 619.36 ;
      RECT 460.2 0.84 460.48 619.36 ;
      RECT 462.44 0.84 462.72 619.36 ;
      RECT 464.68 0.84 464.96 619.36 ;
      RECT 466.92 0.84 467.2 619.36 ;
      RECT 469.16 0.84 469.44 619.36 ;
      RECT 471.4 0.84 471.68 619.36 ;
      RECT 473.64 0.84 473.92 619.36 ;
      RECT 475.88 0.84 476.16 619.36 ;
      RECT 478.12 0.84 478.4 619.36 ;
      RECT 480.36 0.84 480.64 619.36 ;
      RECT 482.6 0.84 482.88 619.36 ;
      RECT 484.84 0.84 485.12 619.36 ;
      RECT 487.08 0.84 487.36 619.36 ;
      RECT 489.32 0.84 489.6 619.36 ;
      RECT 491.56 0.84 491.84 619.36 ;
      RECT 493.8 0.84 494.08 619.36 ;
      RECT 496.04 0.84 496.32 619.36 ;
      RECT 498.28 0.84 498.56 619.36 ;
      RECT 500.52 0.84 500.8 619.36 ;
      RECT 502.76 0.84 503.04 619.36 ;
      RECT 505 0.84 505.28 619.36 ;
      RECT 507.24 0.84 507.52 619.36 ;
      RECT 509.48 0.84 509.76 619.36 ;
      RECT 511.72 0.84 512 619.36 ;
      RECT 513.96 0.84 514.24 619.36 ;
      RECT 516.2 0.84 516.48 619.36 ;
      RECT 518.44 0.84 518.72 619.36 ;
      RECT 520.68 0.84 520.96 619.36 ;
      RECT 522.92 0.84 523.2 619.36 ;
      RECT 525.16 0.84 525.44 619.36 ;
      RECT 527.4 0.84 527.68 619.36 ;
      RECT 529.64 0.84 529.92 619.36 ;
      RECT 531.88 0.84 532.16 619.36 ;
      RECT 534.12 0.84 534.4 619.36 ;
      RECT 536.36 0.84 536.64 619.36 ;
      RECT 538.6 0.84 538.88 619.36 ;
      RECT 540.84 0.84 541.12 619.36 ;
      RECT 543.08 0.84 543.36 619.36 ;
      RECT 545.32 0.84 545.6 619.36 ;
      RECT 547.56 0.84 547.84 619.36 ;
      RECT 549.8 0.84 550.08 619.36 ;
      RECT 552.04 0.84 552.32 619.36 ;
      RECT 554.28 0.84 554.56 619.36 ;
      RECT 556.52 0.84 556.8 619.36 ;
      RECT 558.76 0.84 559.04 619.36 ;
      RECT 561 0.84 561.28 619.36 ;
      RECT 563.24 0.84 563.52 619.36 ;
      RECT 565.48 0.84 565.76 619.36 ;
      RECT 567.72 0.84 568 619.36 ;
      RECT 569.96 0.84 570.24 619.36 ;
      RECT 572.2 0.84 572.48 619.36 ;
      RECT 574.44 0.84 574.72 619.36 ;
      RECT 576.68 0.84 576.96 619.36 ;
      RECT 578.92 0.84 579.2 619.36 ;
      RECT 581.16 0.84 581.44 619.36 ;
      RECT 583.4 0.84 583.68 619.36 ;
      RECT 585.64 0.84 585.92 619.36 ;
      RECT 587.88 0.84 588.16 619.36 ;
      RECT 590.12 0.84 590.4 619.36 ;
      RECT 592.36 0.84 592.64 619.36 ;
      RECT 594.6 0.84 594.88 619.36 ;
      RECT 596.84 0.84 597.12 619.36 ;
      RECT 599.08 0.84 599.36 619.36 ;
      RECT 601.32 0.84 601.6 619.36 ;
      RECT 603.56 0.84 603.84 619.36 ;
      RECT 605.8 0.84 606.08 619.36 ;
      RECT 608.04 0.84 608.32 619.36 ;
      RECT 610.28 0.84 610.56 619.36 ;
      RECT 612.52 0.84 612.8 619.36 ;
      RECT 614.76 0.84 615.04 619.36 ;
      RECT 617 0.84 617.28 619.36 ;
      RECT 619.24 0.84 619.52 619.36 ;
      RECT 621.48 0.84 621.76 619.36 ;
      RECT 623.72 0.84 624 619.36 ;
      RECT 625.96 0.84 626.24 619.36 ;
      RECT 628.2 0.84 628.48 619.36 ;
      RECT 630.44 0.84 630.72 619.36 ;
      RECT 632.68 0.84 632.96 619.36 ;
      RECT 634.92 0.84 635.2 619.36 ;
      RECT 637.16 0.84 637.44 619.36 ;
      RECT 639.4 0.84 639.68 619.36 ;
      RECT 641.64 0.84 641.92 619.36 ;
      RECT 643.88 0.84 644.16 619.36 ;
      RECT 646.12 0.84 646.4 619.36 ;
      RECT 648.36 0.84 648.64 619.36 ;
      RECT 650.6 0.84 650.88 619.36 ;
      RECT 652.84 0.84 653.12 619.36 ;
      RECT 655.08 0.84 655.36 619.36 ;
      RECT 657.32 0.84 657.6 619.36 ;
      RECT 659.56 0.84 659.84 619.36 ;
      RECT 661.8 0.84 662.08 619.36 ;
      RECT 664.04 0.84 664.32 619.36 ;
      RECT 666.28 0.84 666.56 619.36 ;
      RECT 668.52 0.84 668.8 619.36 ;
      RECT 670.76 0.84 671.04 619.36 ;
      RECT 673 0.84 673.28 619.36 ;
      RECT 675.24 0.84 675.52 619.36 ;
      RECT 677.48 0.84 677.76 619.36 ;
      RECT 679.72 0.84 680 619.36 ;
      RECT 681.96 0.84 682.24 619.36 ;
      RECT 684.2 0.84 684.48 619.36 ;
      RECT 686.44 0.84 686.72 619.36 ;
      RECT 688.68 0.84 688.96 619.36 ;
      RECT 690.92 0.84 691.2 619.36 ;
      RECT 693.16 0.84 693.44 619.36 ;
      RECT 695.4 0.84 695.68 619.36 ;
      RECT 697.64 0.84 697.92 619.36 ;
      RECT 699.88 0.84 700.16 619.36 ;
      RECT 702.12 0.84 702.4 619.36 ;
      RECT 704.36 0.84 704.64 619.36 ;
      RECT 706.6 0.84 706.88 619.36 ;
      RECT 708.84 0.84 709.12 619.36 ;
      RECT 711.08 0.84 711.36 619.36 ;
      RECT 713.32 0.84 713.6 619.36 ;
      RECT 715.56 0.84 715.84 619.36 ;
      RECT 717.8 0.84 718.08 619.36 ;
      RECT 720.04 0.84 720.32 619.36 ;
      RECT 722.28 0.84 722.56 619.36 ;
      RECT 724.52 0.84 724.8 619.36 ;
      RECT 726.76 0.84 727.04 619.36 ;
      RECT 729 0.84 729.28 619.36 ;
    END
  END VSS
  PIN VDD
    DIRECTION INOUT ;
    USE POWER ;
    PORT
      LAYER M4 ;
      RECT 2.12 0.84 2.4 619.36 ;
      RECT 4.36 0.84 4.64 619.36 ;
      RECT 6.6 0.84 6.88 619.36 ;
      RECT 8.84 0.84 9.12 619.36 ;
      RECT 11.08 0.84 11.36 619.36 ;
      RECT 13.32 0.84 13.6 619.36 ;
      RECT 15.56 0.84 15.84 619.36 ;
      RECT 17.8 0.84 18.08 619.36 ;
      RECT 20.04 0.84 20.32 619.36 ;
      RECT 22.28 0.84 22.56 619.36 ;
      RECT 24.52 0.84 24.8 619.36 ;
      RECT 26.76 0.84 27.04 619.36 ;
      RECT 29 0.84 29.28 619.36 ;
      RECT 31.24 0.84 31.52 619.36 ;
      RECT 33.48 0.84 33.76 619.36 ;
      RECT 35.72 0.84 36 619.36 ;
      RECT 37.96 0.84 38.24 619.36 ;
      RECT 40.2 0.84 40.48 619.36 ;
      RECT 42.44 0.84 42.72 619.36 ;
      RECT 44.68 0.84 44.96 619.36 ;
      RECT 46.92 0.84 47.2 619.36 ;
      RECT 49.16 0.84 49.44 619.36 ;
      RECT 51.4 0.84 51.68 619.36 ;
      RECT 53.64 0.84 53.92 619.36 ;
      RECT 55.88 0.84 56.16 619.36 ;
      RECT 58.12 0.84 58.4 619.36 ;
      RECT 60.36 0.84 60.64 619.36 ;
      RECT 62.6 0.84 62.88 619.36 ;
      RECT 64.84 0.84 65.12 619.36 ;
      RECT 67.08 0.84 67.36 619.36 ;
      RECT 69.32 0.84 69.6 619.36 ;
      RECT 71.56 0.84 71.84 619.36 ;
      RECT 73.8 0.84 74.08 619.36 ;
      RECT 76.04 0.84 76.32 619.36 ;
      RECT 78.28 0.84 78.56 619.36 ;
      RECT 80.52 0.84 80.8 619.36 ;
      RECT 82.76 0.84 83.04 619.36 ;
      RECT 85 0.84 85.28 619.36 ;
      RECT 87.24 0.84 87.52 619.36 ;
      RECT 89.48 0.84 89.76 619.36 ;
      RECT 91.72 0.84 92 619.36 ;
      RECT 93.96 0.84 94.24 619.36 ;
      RECT 96.2 0.84 96.48 619.36 ;
      RECT 98.44 0.84 98.72 619.36 ;
      RECT 100.68 0.84 100.96 619.36 ;
      RECT 102.92 0.84 103.2 619.36 ;
      RECT 105.16 0.84 105.44 619.36 ;
      RECT 107.4 0.84 107.68 619.36 ;
      RECT 109.64 0.84 109.92 619.36 ;
      RECT 111.88 0.84 112.16 619.36 ;
      RECT 114.12 0.84 114.4 619.36 ;
      RECT 116.36 0.84 116.64 619.36 ;
      RECT 118.6 0.84 118.88 619.36 ;
      RECT 120.84 0.84 121.12 619.36 ;
      RECT 123.08 0.84 123.36 619.36 ;
      RECT 125.32 0.84 125.6 619.36 ;
      RECT 127.56 0.84 127.84 619.36 ;
      RECT 129.8 0.84 130.08 619.36 ;
      RECT 132.04 0.84 132.32 619.36 ;
      RECT 134.28 0.84 134.56 619.36 ;
      RECT 136.52 0.84 136.8 619.36 ;
      RECT 138.76 0.84 139.04 619.36 ;
      RECT 141 0.84 141.28 619.36 ;
      RECT 143.24 0.84 143.52 619.36 ;
      RECT 145.48 0.84 145.76 619.36 ;
      RECT 147.72 0.84 148 619.36 ;
      RECT 149.96 0.84 150.24 619.36 ;
      RECT 152.2 0.84 152.48 619.36 ;
      RECT 154.44 0.84 154.72 619.36 ;
      RECT 156.68 0.84 156.96 619.36 ;
      RECT 158.92 0.84 159.2 619.36 ;
      RECT 161.16 0.84 161.44 619.36 ;
      RECT 163.4 0.84 163.68 619.36 ;
      RECT 165.64 0.84 165.92 619.36 ;
      RECT 167.88 0.84 168.16 619.36 ;
      RECT 170.12 0.84 170.4 619.36 ;
      RECT 172.36 0.84 172.64 619.36 ;
      RECT 174.6 0.84 174.88 619.36 ;
      RECT 176.84 0.84 177.12 619.36 ;
      RECT 179.08 0.84 179.36 619.36 ;
      RECT 181.32 0.84 181.6 619.36 ;
      RECT 183.56 0.84 183.84 619.36 ;
      RECT 185.8 0.84 186.08 619.36 ;
      RECT 188.04 0.84 188.32 619.36 ;
      RECT 190.28 0.84 190.56 619.36 ;
      RECT 192.52 0.84 192.8 619.36 ;
      RECT 194.76 0.84 195.04 619.36 ;
      RECT 197 0.84 197.28 619.36 ;
      RECT 199.24 0.84 199.52 619.36 ;
      RECT 201.48 0.84 201.76 619.36 ;
      RECT 203.72 0.84 204 619.36 ;
      RECT 205.96 0.84 206.24 619.36 ;
      RECT 208.2 0.84 208.48 619.36 ;
      RECT 210.44 0.84 210.72 619.36 ;
      RECT 212.68 0.84 212.96 619.36 ;
      RECT 214.92 0.84 215.2 619.36 ;
      RECT 217.16 0.84 217.44 619.36 ;
      RECT 219.4 0.84 219.68 619.36 ;
      RECT 221.64 0.84 221.92 619.36 ;
      RECT 223.88 0.84 224.16 619.36 ;
      RECT 226.12 0.84 226.4 619.36 ;
      RECT 228.36 0.84 228.64 619.36 ;
      RECT 230.6 0.84 230.88 619.36 ;
      RECT 232.84 0.84 233.12 619.36 ;
      RECT 235.08 0.84 235.36 619.36 ;
      RECT 237.32 0.84 237.6 619.36 ;
      RECT 239.56 0.84 239.84 619.36 ;
      RECT 241.8 0.84 242.08 619.36 ;
      RECT 244.04 0.84 244.32 619.36 ;
      RECT 246.28 0.84 246.56 619.36 ;
      RECT 248.52 0.84 248.8 619.36 ;
      RECT 250.76 0.84 251.04 619.36 ;
      RECT 253 0.84 253.28 619.36 ;
      RECT 255.24 0.84 255.52 619.36 ;
      RECT 257.48 0.84 257.76 619.36 ;
      RECT 259.72 0.84 260 619.36 ;
      RECT 261.96 0.84 262.24 619.36 ;
      RECT 264.2 0.84 264.48 619.36 ;
      RECT 266.44 0.84 266.72 619.36 ;
      RECT 268.68 0.84 268.96 619.36 ;
      RECT 270.92 0.84 271.2 619.36 ;
      RECT 273.16 0.84 273.44 619.36 ;
      RECT 275.4 0.84 275.68 619.36 ;
      RECT 277.64 0.84 277.92 619.36 ;
      RECT 279.88 0.84 280.16 619.36 ;
      RECT 282.12 0.84 282.4 619.36 ;
      RECT 284.36 0.84 284.64 619.36 ;
      RECT 286.6 0.84 286.88 619.36 ;
      RECT 288.84 0.84 289.12 619.36 ;
      RECT 291.08 0.84 291.36 619.36 ;
      RECT 293.32 0.84 293.6 619.36 ;
      RECT 295.56 0.84 295.84 619.36 ;
      RECT 297.8 0.84 298.08 619.36 ;
      RECT 300.04 0.84 300.32 619.36 ;
      RECT 302.28 0.84 302.56 619.36 ;
      RECT 304.52 0.84 304.8 619.36 ;
      RECT 306.76 0.84 307.04 619.36 ;
      RECT 309 0.84 309.28 619.36 ;
      RECT 311.24 0.84 311.52 619.36 ;
      RECT 313.48 0.84 313.76 619.36 ;
      RECT 315.72 0.84 316 619.36 ;
      RECT 317.96 0.84 318.24 619.36 ;
      RECT 320.2 0.84 320.48 619.36 ;
      RECT 322.44 0.84 322.72 619.36 ;
      RECT 324.68 0.84 324.96 619.36 ;
      RECT 326.92 0.84 327.2 619.36 ;
      RECT 329.16 0.84 329.44 619.36 ;
      RECT 331.4 0.84 331.68 619.36 ;
      RECT 333.64 0.84 333.92 619.36 ;
      RECT 335.88 0.84 336.16 619.36 ;
      RECT 338.12 0.84 338.4 619.36 ;
      RECT 340.36 0.84 340.64 619.36 ;
      RECT 342.6 0.84 342.88 619.36 ;
      RECT 344.84 0.84 345.12 619.36 ;
      RECT 347.08 0.84 347.36 619.36 ;
      RECT 349.32 0.84 349.6 619.36 ;
      RECT 351.56 0.84 351.84 619.36 ;
      RECT 353.8 0.84 354.08 619.36 ;
      RECT 356.04 0.84 356.32 619.36 ;
      RECT 358.28 0.84 358.56 619.36 ;
      RECT 360.52 0.84 360.8 619.36 ;
      RECT 362.76 0.84 363.04 619.36 ;
      RECT 365 0.84 365.28 619.36 ;
      RECT 367.24 0.84 367.52 619.36 ;
      RECT 369.48 0.84 369.76 619.36 ;
      RECT 371.72 0.84 372 619.36 ;
      RECT 373.96 0.84 374.24 619.36 ;
      RECT 376.2 0.84 376.48 619.36 ;
      RECT 378.44 0.84 378.72 619.36 ;
      RECT 380.68 0.84 380.96 619.36 ;
      RECT 382.92 0.84 383.2 619.36 ;
      RECT 385.16 0.84 385.44 619.36 ;
      RECT 387.4 0.84 387.68 619.36 ;
      RECT 389.64 0.84 389.92 619.36 ;
      RECT 391.88 0.84 392.16 619.36 ;
      RECT 394.12 0.84 394.4 619.36 ;
      RECT 396.36 0.84 396.64 619.36 ;
      RECT 398.6 0.84 398.88 619.36 ;
      RECT 400.84 0.84 401.12 619.36 ;
      RECT 403.08 0.84 403.36 619.36 ;
      RECT 405.32 0.84 405.6 619.36 ;
      RECT 407.56 0.84 407.84 619.36 ;
      RECT 409.8 0.84 410.08 619.36 ;
      RECT 412.04 0.84 412.32 619.36 ;
      RECT 414.28 0.84 414.56 619.36 ;
      RECT 416.52 0.84 416.8 619.36 ;
      RECT 418.76 0.84 419.04 619.36 ;
      RECT 421 0.84 421.28 619.36 ;
      RECT 423.24 0.84 423.52 619.36 ;
      RECT 425.48 0.84 425.76 619.36 ;
      RECT 427.72 0.84 428 619.36 ;
      RECT 429.96 0.84 430.24 619.36 ;
      RECT 432.2 0.84 432.48 619.36 ;
      RECT 434.44 0.84 434.72 619.36 ;
      RECT 436.68 0.84 436.96 619.36 ;
      RECT 438.92 0.84 439.2 619.36 ;
      RECT 441.16 0.84 441.44 619.36 ;
      RECT 443.4 0.84 443.68 619.36 ;
      RECT 445.64 0.84 445.92 619.36 ;
      RECT 447.88 0.84 448.16 619.36 ;
      RECT 450.12 0.84 450.4 619.36 ;
      RECT 452.36 0.84 452.64 619.36 ;
      RECT 454.6 0.84 454.88 619.36 ;
      RECT 456.84 0.84 457.12 619.36 ;
      RECT 459.08 0.84 459.36 619.36 ;
      RECT 461.32 0.84 461.6 619.36 ;
      RECT 463.56 0.84 463.84 619.36 ;
      RECT 465.8 0.84 466.08 619.36 ;
      RECT 468.04 0.84 468.32 619.36 ;
      RECT 470.28 0.84 470.56 619.36 ;
      RECT 472.52 0.84 472.8 619.36 ;
      RECT 474.76 0.84 475.04 619.36 ;
      RECT 477 0.84 477.28 619.36 ;
      RECT 479.24 0.84 479.52 619.36 ;
      RECT 481.48 0.84 481.76 619.36 ;
      RECT 483.72 0.84 484 619.36 ;
      RECT 485.96 0.84 486.24 619.36 ;
      RECT 488.2 0.84 488.48 619.36 ;
      RECT 490.44 0.84 490.72 619.36 ;
      RECT 492.68 0.84 492.96 619.36 ;
      RECT 494.92 0.84 495.2 619.36 ;
      RECT 497.16 0.84 497.44 619.36 ;
      RECT 499.4 0.84 499.68 619.36 ;
      RECT 501.64 0.84 501.92 619.36 ;
      RECT 503.88 0.84 504.16 619.36 ;
      RECT 506.12 0.84 506.4 619.36 ;
      RECT 508.36 0.84 508.64 619.36 ;
      RECT 510.6 0.84 510.88 619.36 ;
      RECT 512.84 0.84 513.12 619.36 ;
      RECT 515.08 0.84 515.36 619.36 ;
      RECT 517.32 0.84 517.6 619.36 ;
      RECT 519.56 0.84 519.84 619.36 ;
      RECT 521.8 0.84 522.08 619.36 ;
      RECT 524.04 0.84 524.32 619.36 ;
      RECT 526.28 0.84 526.56 619.36 ;
      RECT 528.52 0.84 528.8 619.36 ;
      RECT 530.76 0.84 531.04 619.36 ;
      RECT 533 0.84 533.28 619.36 ;
      RECT 535.24 0.84 535.52 619.36 ;
      RECT 537.48 0.84 537.76 619.36 ;
      RECT 539.72 0.84 540 619.36 ;
      RECT 541.96 0.84 542.24 619.36 ;
      RECT 544.2 0.84 544.48 619.36 ;
      RECT 546.44 0.84 546.72 619.36 ;
      RECT 548.68 0.84 548.96 619.36 ;
      RECT 550.92 0.84 551.2 619.36 ;
      RECT 553.16 0.84 553.44 619.36 ;
      RECT 555.4 0.84 555.68 619.36 ;
      RECT 557.64 0.84 557.92 619.36 ;
      RECT 559.88 0.84 560.16 619.36 ;
      RECT 562.12 0.84 562.4 619.36 ;
      RECT 564.36 0.84 564.64 619.36 ;
      RECT 566.6 0.84 566.88 619.36 ;
      RECT 568.84 0.84 569.12 619.36 ;
      RECT 571.08 0.84 571.36 619.36 ;
      RECT 573.32 0.84 573.6 619.36 ;
      RECT 575.56 0.84 575.84 619.36 ;
      RECT 577.8 0.84 578.08 619.36 ;
      RECT 580.04 0.84 580.32 619.36 ;
      RECT 582.28 0.84 582.56 619.36 ;
      RECT 584.52 0.84 584.8 619.36 ;
      RECT 586.76 0.84 587.04 619.36 ;
      RECT 589 0.84 589.28 619.36 ;
      RECT 591.24 0.84 591.52 619.36 ;
      RECT 593.48 0.84 593.76 619.36 ;
      RECT 595.72 0.84 596 619.36 ;
      RECT 597.96 0.84 598.24 619.36 ;
      RECT 600.2 0.84 600.48 619.36 ;
      RECT 602.44 0.84 602.72 619.36 ;
      RECT 604.68 0.84 604.96 619.36 ;
      RECT 606.92 0.84 607.2 619.36 ;
      RECT 609.16 0.84 609.44 619.36 ;
      RECT 611.4 0.84 611.68 619.36 ;
      RECT 613.64 0.84 613.92 619.36 ;
      RECT 615.88 0.84 616.16 619.36 ;
      RECT 618.12 0.84 618.4 619.36 ;
      RECT 620.36 0.84 620.64 619.36 ;
      RECT 622.6 0.84 622.88 619.36 ;
      RECT 624.84 0.84 625.12 619.36 ;
      RECT 627.08 0.84 627.36 619.36 ;
      RECT 629.32 0.84 629.6 619.36 ;
      RECT 631.56 0.84 631.84 619.36 ;
      RECT 633.8 0.84 634.08 619.36 ;
      RECT 636.04 0.84 636.32 619.36 ;
      RECT 638.28 0.84 638.56 619.36 ;
      RECT 640.52 0.84 640.8 619.36 ;
      RECT 642.76 0.84 643.04 619.36 ;
      RECT 645 0.84 645.28 619.36 ;
      RECT 647.24 0.84 647.52 619.36 ;
      RECT 649.48 0.84 649.76 619.36 ;
      RECT 651.72 0.84 652 619.36 ;
      RECT 653.96 0.84 654.24 619.36 ;
      RECT 656.2 0.84 656.48 619.36 ;
      RECT 658.44 0.84 658.72 619.36 ;
      RECT 660.68 0.84 660.96 619.36 ;
      RECT 662.92 0.84 663.2 619.36 ;
      RECT 665.16 0.84 665.44 619.36 ;
      RECT 667.4 0.84 667.68 619.36 ;
      RECT 669.64 0.84 669.92 619.36 ;
      RECT 671.88 0.84 672.16 619.36 ;
      RECT 674.12 0.84 674.4 619.36 ;
      RECT 676.36 0.84 676.64 619.36 ;
      RECT 678.6 0.84 678.88 619.36 ;
      RECT 680.84 0.84 681.12 619.36 ;
      RECT 683.08 0.84 683.36 619.36 ;
      RECT 685.32 0.84 685.6 619.36 ;
      RECT 687.56 0.84 687.84 619.36 ;
      RECT 689.8 0.84 690.08 619.36 ;
      RECT 692.04 0.84 692.32 619.36 ;
      RECT 694.28 0.84 694.56 619.36 ;
      RECT 696.52 0.84 696.8 619.36 ;
      RECT 698.76 0.84 699.04 619.36 ;
      RECT 701 0.84 701.28 619.36 ;
      RECT 703.24 0.84 703.52 619.36 ;
      RECT 705.48 0.84 705.76 619.36 ;
      RECT 707.72 0.84 708 619.36 ;
      RECT 709.96 0.84 710.24 619.36 ;
      RECT 712.2 0.84 712.48 619.36 ;
      RECT 714.44 0.84 714.72 619.36 ;
      RECT 716.68 0.84 716.96 619.36 ;
      RECT 718.92 0.84 719.2 619.36 ;
      RECT 721.16 0.84 721.44 619.36 ;
      RECT 723.4 0.84 723.68 619.36 ;
      RECT 725.64 0.84 725.92 619.36 ;
      RECT 727.88 0.84 728.16 619.36 ;
      RECT 730.12 0.84 730.4 619.36 ;
    END
  END VDD
  OBS
    LAYER M1 ;
    RECT 0 0 730.55 620.2 ;
    LAYER M2 ;
    RECT 0 0 730.55 620.2 ;
  END
END ht45_rocketgemmini_mem_1_ext_bottom

END LIBRARY
